VERSION 5.7 ;
  NOWIREEXTENSIONATPIN ON ;
  DIVIDERCHAR "/" ;
  BUSBITCHARS "[]" ;
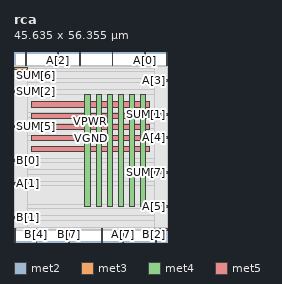
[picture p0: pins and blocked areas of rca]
MACRO rca
  CLASS BLOCK ;
  FOREIGN rca ;
  ORIGIN 0.000 0.000 ;
  SIZE 45.635 BY 56.355 ;
  PIN A[0]
    DIRECTION INPUT ;
    USE SIGNAL ;
    ANTENNAGATEAREA 0.126000 ;
    PORT
      LAYER met2 ;
        RECT 38.730 52.355 39.010 56.355 ;
    END
  END A[0]
  PIN A[1]
    DIRECTION INPUT ;
    USE SIGNAL ;
    ANTENNAGATEAREA 0.196500 ;
    PORT
      LAYER met3 ;
        RECT 0.000 17.040 4.000 17.640 ;
    END
  END A[1]
  PIN A[2]
    DIRECTION INPUT ;
    USE SIGNAL ;
    ANTENNAGATEAREA 0.196500 ;
    PORT
      LAYER met2 ;
        RECT 12.970 52.355 13.250 56.355 ;
    END
  END A[2]
  PIN A[3]
    DIRECTION INPUT ;
    USE SIGNAL ;
    ANTENNAGATEAREA 0.196500 ;
    PORT
      LAYER met3 ;
        RECT 41.635 47.640 45.635 48.240 ;
    END
  END A[3]
  PIN A[4]
    DIRECTION INPUT ;
    USE SIGNAL ;
    ANTENNAGATEAREA 0.196500 ;
    PORT
      LAYER met3 ;
        RECT 41.635 30.640 45.635 31.240 ;
    END
  END A[4]
  PIN A[5]
    DIRECTION INPUT ;
    USE SIGNAL ;
    ANTENNAGATEAREA 0.196500 ;
    PORT
      LAYER met3 ;
        RECT 41.635 10.240 45.635 10.840 ;
    END
  END A[5]
  PIN A[6]
    DIRECTION INPUT ;
    USE SIGNAL ;
    ANTENNAGATEAREA 0.196500 ;
    PORT
      LAYER met2 ;
        RECT 45.170 52.355 45.450 56.355 ;
    END
  END A[6]
  PIN A[7]
    DIRECTION INPUT ;
    USE SIGNAL ;
    ANTENNAGATEAREA 0.196500 ;
    PORT
      LAYER met2 ;
        RECT 32.290 0.000 32.570 4.000 ;
    END
  END A[7]
  PIN B[0]
    DIRECTION INPUT ;
    USE SIGNAL ;
    ANTENNAGATEAREA 0.196500 ;
    PORT
      LAYER met3 ;
        RECT 0.000 23.840 4.000 24.440 ;
    END
  END B[0]
  PIN B[1]
    DIRECTION INPUT ;
    USE SIGNAL ;
    ANTENNAGATEAREA 0.196500 ;
    PORT
      LAYER met3 ;
        RECT 0.000 6.840 4.000 7.440 ;
    END
  END B[1]
  PIN B[2]
    DIRECTION INPUT ;
    USE SIGNAL ;
    ANTENNAGATEAREA 0.196500 ;
    PORT
      LAYER met2 ;
        RECT 41.950 0.000 42.230 4.000 ;
    END
  END B[2]
  PIN B[3]
    DIRECTION INPUT ;
    USE SIGNAL ;
    ANTENNAGATEAREA 0.196500 ;
    PORT
      LAYER met2 ;
        RECT 0.090 0.000 0.370 4.000 ;
    END
  END B[3]
  PIN B[4]
    DIRECTION INPUT ;
    USE SIGNAL ;
    ANTENNAGATEAREA 0.196500 ;
    PORT
      LAYER met2 ;
        RECT 6.530 0.000 6.810 4.000 ;
    END
  END B[4]
  PIN B[5]
    DIRECTION INPUT ;
    USE SIGNAL ;
    ANTENNAGATEAREA 0.196500 ;
    PORT
      LAYER met2 ;
        RECT 19.410 52.355 19.690 56.355 ;
    END
  END B[5]
  PIN B[6]
    DIRECTION INPUT ;
    USE SIGNAL ;
    ANTENNAGATEAREA 0.196500 ;
    PORT
      LAYER met3 ;
        RECT 41.635 3.440 45.635 4.040 ;
    END
  END B[6]
  PIN B[7]
    DIRECTION INPUT ;
    USE SIGNAL ;
    ANTENNAGATEAREA 0.196500 ;
    PORT
      LAYER met2 ;
        RECT 16.190 0.000 16.470 4.000 ;
    END
  END B[7]
  PIN SUM[0]
    DIRECTION OUTPUT TRISTATE ;
    USE SIGNAL ;
    ANTENNADIFFAREA 0.795200 ;
    PORT
      LAYER met2 ;
        RECT 3.310 52.355 3.590 56.355 ;
    END
  END SUM[0]
  PIN SUM[1]
    DIRECTION OUTPUT TRISTATE ;
    USE SIGNAL ;
    ANTENNADIFFAREA 0.445500 ;
    PORT
      LAYER met3 ;
        RECT 41.635 37.440 45.635 38.040 ;
    END
  END SUM[1]
  PIN SUM[2]
    DIRECTION OUTPUT TRISTATE ;
    USE SIGNAL ;
    ANTENNADIFFAREA 0.795200 ;
    PORT
      LAYER met3 ;
        RECT 0.000 44.240 4.000 44.840 ;
    END
  END SUM[2]
  PIN SUM[3]
    DIRECTION OUTPUT TRISTATE ;
    USE SIGNAL ;
    ANTENNADIFFAREA 0.795200 ;
    PORT
      LAYER met2 ;
        RECT 29.070 52.355 29.350 56.355 ;
    END
  END SUM[3]
  PIN SUM[4]
    DIRECTION OUTPUT TRISTATE ;
    USE SIGNAL ;
    ANTENNADIFFAREA 0.795200 ;
    PORT
      LAYER met2 ;
        RECT 25.850 0.000 26.130 4.000 ;
    END
  END SUM[4]
  PIN SUM[5]
    DIRECTION OUTPUT TRISTATE ;
    USE SIGNAL ;
    ANTENNADIFFAREA 0.795200 ;
    PORT
      LAYER met3 ;
        RECT 0.000 34.040 4.000 34.640 ;
    END
  END SUM[5]
  PIN SUM[6]
    DIRECTION OUTPUT TRISTATE ;
    USE SIGNAL ;
    ANTENNADIFFAREA 0.891000 ;
    PORT
      LAYER met3 ;
        RECT 0.000 51.040 4.000 51.640 ;
    END
  END SUM[6]
  PIN SUM[7]
    DIRECTION OUTPUT TRISTATE ;
    USE SIGNAL ;
    ANTENNADIFFAREA 0.445500 ;
    PORT
      LAYER met3 ;
        RECT 41.635 20.440 45.635 21.040 ;
    END
  END SUM[7]
  PIN VGND
    DIRECTION INOUT ;
    USE GROUND ;
    PORT
      LAYER met4 ;
        RECT 24.340 10.640 25.940 43.760 ;
    END
    PORT
      LAYER met4 ;
        RECT 30.940 10.640 32.540 43.760 ;
    END
    PORT
      LAYER met4 ;
        RECT 37.540 10.640 39.140 43.760 ;
    END
    PORT
      LAYER met5 ;
        RECT 5.280 30.030 40.260 31.630 ;
    END
    PORT
      LAYER met5 ;
        RECT 5.280 36.630 40.260 38.230 ;
    END
  END VGND
  PIN VPWR
    DIRECTION INOUT ;
    USE POWER ;
    PORT
      LAYER met4 ;
        RECT 21.040 10.640 22.640 43.760 ;
    END
    PORT
      LAYER met4 ;
        RECT 27.640 10.640 29.240 43.760 ;
    END
    PORT
      LAYER met4 ;
        RECT 34.240 10.640 35.840 43.760 ;
    END
    PORT
      LAYER met5 ;
        RECT 5.280 26.730 40.260 28.330 ;
    END
    PORT
      LAYER met5 ;
        RECT 5.280 33.330 40.260 34.930 ;
    END
    PORT
      LAYER met5 ;
        RECT 5.280 39.930 40.260 41.530 ;
    END
  END VPWR
  OBS
      LAYER li1 ;
        RECT 5.520 10.795 40.020 43.605 ;
      LAYER met1 ;
        RECT 0.070 10.640 45.470 43.760 ;
      LAYER met2 ;
        RECT 0.100 52.075 3.030 52.355 ;
        RECT 3.870 52.075 12.690 52.355 ;
        RECT 13.530 52.075 19.130 52.355 ;
        RECT 19.970 52.075 28.790 52.355 ;
        RECT 29.630 52.075 38.450 52.355 ;
        RECT 39.290 52.075 44.890 52.355 ;
        RECT 0.100 4.280 45.440 52.075 ;
        RECT 0.650 3.555 6.250 4.280 ;
        RECT 7.090 3.555 15.910 4.280 ;
        RECT 16.750 3.555 25.570 4.280 ;
        RECT 26.410 3.555 32.010 4.280 ;
        RECT 32.850 3.555 41.670 4.280 ;
        RECT 42.510 3.555 45.440 4.280 ;
      LAYER met3 ;
        RECT 4.400 50.640 41.635 51.505 ;
        RECT 4.000 48.640 41.635 50.640 ;
        RECT 4.000 47.240 41.235 48.640 ;
        RECT 4.000 45.240 41.635 47.240 ;
        RECT 4.400 43.840 41.635 45.240 ;
        RECT 4.000 38.440 41.635 43.840 ;
        RECT 4.000 37.040 41.235 38.440 ;
        RECT 4.000 35.040 41.635 37.040 ;
        RECT 4.400 33.640 41.635 35.040 ;
        RECT 4.000 31.640 41.635 33.640 ;
        RECT 4.000 30.240 41.235 31.640 ;
        RECT 4.000 24.840 41.635 30.240 ;
        RECT 4.400 23.440 41.635 24.840 ;
        RECT 4.000 21.440 41.635 23.440 ;
        RECT 4.000 20.040 41.235 21.440 ;
        RECT 4.000 18.040 41.635 20.040 ;
        RECT 4.400 16.640 41.635 18.040 ;
        RECT 4.000 11.240 41.635 16.640 ;
        RECT 4.000 9.840 41.235 11.240 ;
        RECT 4.000 7.840 41.635 9.840 ;
        RECT 4.400 6.440 41.635 7.840 ;
        RECT 4.000 4.440 41.635 6.440 ;
        RECT 4.000 3.575 41.235 4.440 ;
  END
END rca
END LIBRARY

